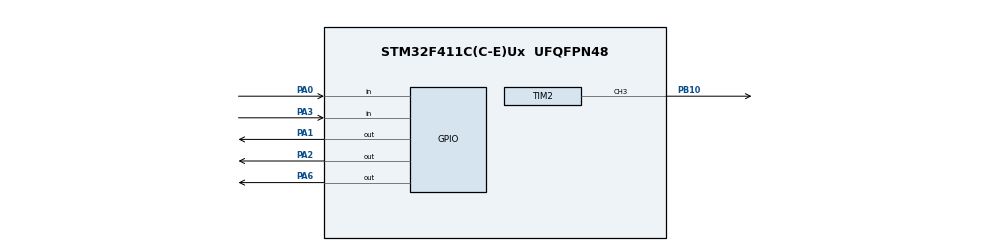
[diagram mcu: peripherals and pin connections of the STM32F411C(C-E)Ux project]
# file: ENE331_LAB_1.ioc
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Mcu.Family=STM32F4
Mcu.Name=STM32F411C(C-E)Ux
Mcu.Package=UFQFPN48
NVIC.PriorityGroup=NVIC_PRIORITYGROUP_4
NVIC.TIM2_IRQn=true\:0\:0\:false\:false\:true\:true\:true\:true
PA0-WKUP.Signal=GPIO_Input
PA1.Signal=GPIO_Output
PA13.Mode=Serial_Wire
PA13.Signal=SYS_JTMS-SWDIO
PA14.Mode=Serial_Wire
PA14.Signal=SYS_JTCK-SWCLK
PA2.Signal=GPIO_Output
PA3.Signal=GPIO_Input
PA6.PinState=GPIO_PIN_RESET
PA6.Signal=GPIO_Output
PB10.Signal=S_TIM2_CH3
PH0\ -\ OSC_IN.Mode=HSE-External-Oscillator
PH0\ -\ OSC_IN.Signal=RCC_OSC_IN
PH1\ -\ OSC_OUT.Mode=HSE-External-Oscillator
PH1\ -\ OSC_OUT.Signal=RCC_OSC_OUT
ProjectManager.HeapSize=0x200
ProjectManager.StackSize=0x400
ProjectManager.TargetToolchain=STM32CubeIDE
RCC.48MHZClocksFreq_Value=37500000
RCC.AHBFreq_Value=75000000
RCC.APB1CLKDivider=RCC_HCLK_DIV2
RCC.APB1Freq_Value=37500000
RCC.APB1TimFreq_Value=75000000
RCC.APB2Freq_Value=75000000
RCC.APB2TimFreq_Value=75000000
RCC.CortexFreq_Value=75000000
RCC.HCLKFreq_Value=75000000
RCC.HSE_VALUE=25000000
RCC.HSI_VALUE=16000000
RCC.LSE_VALUE=32768
RCC.PLLM=12
RCC.PLLN=72
RCC.PLLSourceVirtual=RCC_PLLSOURCE_HSE
RCC.SYSCLKFreq_VALUE=75000000
RCC.SYSCLKSource=RCC_SYSCLKSOURCE_PLLCLK
RCC.VCOOutputFreq_Value=150000000
SH.S_TIM2_CH3.0=TIM2_CH3,PWM Generation3 CH3
TIM2.Channel-PWM\ Generation3\ CH3=TIM_CHANNEL_3
TIM2.Period=1
TIM2.Prescaler=144-1
VP_TIM2_VS_ClockSourceINT.Mode=Internal
board=custom

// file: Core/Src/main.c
/* USER CODE BEGIN Header */
/**
  ******************************************************************************
  * @file           : main.c
  * @brief          : Main program body
  ******************************************************************************
  * @attention
  *
  * Copyright (c) 2025 STMicroelectronics.
  * All rights reserved.
  *
  * This software is licensed under terms that can be found in the LICENSE file
  * in the root directory of this software component.
  * If no LICENSE file comes with this software, it is provided AS-IS.
  *
  ******************************************************************************
  */
/* USER CODE END Header */
#include "main.h"

/* USER CODE BEGIN PM */
uint32_t Time_1;
uint32_t Settime_1 = 60; // กำหนดเวลาในการกระพริบ PA6 ทุกๆ 60 ticks (1.2 ms) , จากการคำนวณในรูป

uint32_t Time_2;
uint32_t Settime_2 = 1500;  // กำหนดเวลาในการอ่านค่าปุ่มทุกๆ 1500 ticks (20 ms)

uint32_t counter = 0; // นับเวลาโดยใช้ Timer

uint8_t state = 0;
uint8_t LUT[4] = {
	    0b001,  // State 0 → PA1 ON
	    0b010,  // State 1 → PA2 ON
	    0b100,  // State 2 → PA3 ON
	    0b111   // State 3 → All ON
};

void GPIOA_Config(void) {
	// Enable GPIOA Clock (if not already done)
	RCC->AHB1ENR |= RCC_AHB1ENR_GPIOAEN;

	// PA1–PA3: Set as general-purpose output
	GPIOA->MODER &= ~((0x3 << (1 * 2)) | (0x3 << (2 * 2)) | (0x3 << (3 * 2)));
	GPIOA->MODER |=  ((0x1 << (1 * 2)) | (0x1 << (2 * 2)) | (0x1 << (3 * 2))); // '01' = output

	// PA6
	GPIOA->MODER &= ~(0x3 << (6 * 2));  // Clear MODER6
	GPIOA->MODER |=  (0x2 << (6 * 2));  // '10'

	// Set ให้ output type ให้เป็น push-pull สำหรับ PA1, PA2, PA3, PA6
	GPIOA->OTYPER &= ~((1 << 1) | (1 << 2) | (1 << 3) | (1 << 6));

	// Set ให้ PA1, PA2, PA3, PA6 ให้ไม่มี pull-up หรือ pull-down
	GPIOA->PUPDR &= ~((0x3 << (1 * 2)) | (0x3 << (2 * 2)) | (0x3 << (3 * 2)) | (0x3 << (6 * 2)));

	// PA6 bits 27:24
	GPIOA->AFR[0] &= ~(0xF << (6 * 4));
	GPIOA->AFR[0] |=  (0x1 << (6 * 4));  // AF1
}
unsigned char Read_PA0(void) {
	return (GPIOA->IDR & (1 << 0)) ? 1 : 0; // ถ้า PA0 = 1(กด) คืนค่า 1, ถ้า PA0 = 0 คืนค่า 0
}

void GPIOB_Config(void) {
    // Enable GPIOB clock
    RCC->AHB1ENR |= (1 << 1);

    // MODER10 = B10
    GPIOB->MODER &= ~(0x3 << 20);  // Clear bits สำหรับ 21:20
    GPIOB->MODER |=  (0x2 << 20);  // Set bits 21:20 to 10

    // Set Alternate Function AF1 for TIM2_CH3 on PB10
    GPIOB->AFR[1] &= ~(0xF << 8);  // Clear bits สำหรับ PB10
    GPIOB->AFR[1] |=  (0x1 << 8);  // TIM2_CH3

    // Set push-pull and no pull-up/down
    GPIOB->OTYPER &= ~(1 << 10);    // Push-pull
    GPIOB->PUPDR  &= ~(0x3 << 20);  // No pull
}

void GPIO_Toggle_Config(void) {
    // Enable GPIOA Clock
    RCC -> AHB1ENR |= (0x01 << 0);  // Enable GPIOA clock

    // Set PA6 as output
    GPIOA -> MODER &= ~(0x03 << (6 * 2));  // Clear MODER6
    GPIOA -> MODER |= (0x01 << (6 * 2));   // Set PA6 as output ('01')

    // Set output type
    GPIOA -> OTYPER &= ~(0x01 << 6);  // set PA6 เป็น push-pull

    // Set GPIO Speed (optional)
    GPIOA -> OSPEEDR &= ~(0x03 << (6 * 2));  // set PA6 เป็นความเร็วต่ำ (default)

    // Disable pull-up/pull-down
    GPIOA -> PUPDR &= ~(0x03 << (6 * 2));   // ไม่มี pull-up หรือ pull-down สำหรับ PA6
}

void HAL_TIM_PeriodElapsedCallback(TIM_HandleTypeDef* htim) {
	if(htim -> Instance == TIM2) {
		counter++;
	}
}

/* USER CODE END PM */

TIM_HandleTypeDef htim2;

void SystemClock_Config(void);
static void MX_GPIO_Init(void);
static void MX_TIM2_Init(void);

int main(void)
{

  /* MCU Configuration--------------------------------------------------------*/

  /* Reset of all peripherals, Initializes the Flash interface and the Systick. */
  HAL_Init();

  /* Configure the system clock */
  SystemClock_Config();

  /* Initialize all configured peripherals */
  MX_GPIO_Init();
  MX_TIM2_Init();
  /* USER CODE BEGIN 2 */
  HAL_TIM_Base_Start(&htim2);
  GPIOA_Config();
  GPIOB_Config();
  GPIO_Toggle_Config();

  /* USER CODE END 2 */

  /* Infinite loop */
  /* USER CODE BEGIN WHILE */
  while (1)
  {

	     // 20 us base time from TIM2
	     if (__HAL_TIM_GET_FLAG(&htim2, TIM_FLAG_UPDATE) == SET) {
	         __HAL_TIM_CLEAR_FLAG(&htim2, TIM_FLAG_UPDATE);
	         counter++;
	     }
	        // ให้ PA6 กระพิบทุกๆ 1.2 ms
  	        if((counter - Time_1) >= Settime_1) {
	            // Your program task
	        	GPIOA-> ODR ^= (1 << 6); // Toggle PA6
	        	for(uint32_t i=0; i<=60000; i++) { // รอเวลาให้กระพริบ
	        		__NOP();
	        	}
	            Time_1 = counter; // update
		    }

	        // อ่านค่า PA0 และเปลี่ยน state ใน LUT
	        if((counter - Time_2) >= Settime_2) {
	            // Your program task
	        	 if ((Read_PA0() == 0 )) {
	        		// On falling edge (button press)
	        		GPIOA->ODR &= ~(0x0E);               // Clear ค่า PA1–PA3
	        		GPIOA->ODR |= (LUT[state] << 1);     // Update LED

	        		state += 1;

	        		if (state == 4){ // ถ้าเกิน state 3 reset ไป 0 ใหม่
	        			state = 0;}
	        		     	             }
	            Time_2 = counter; // update
		    }

    /* USER CODE END WHILE */

  }
}

void SystemClock_Config(void)
{
  RCC_OscInitTypeDef RCC_OscInitStruct = {0};
  RCC_ClkInitTypeDef RCC_ClkInitStruct = {0};

  /** Configure the main internal regulator output voltage
  */
  __HAL_RCC_PWR_CLK_ENABLE();
  __HAL_PWR_VOLTAGESCALING_CONFIG(PWR_REGULATOR_VOLTAGE_SCALE1);

  /** Initializes the RCC Oscillators according to the specified parameters
  * in the RCC_OscInitTypeDef structure.
  */
  RCC_OscInitStruct.OscillatorType = RCC_OSCILLATORTYPE_HSI;
  RCC_OscInitStruct.HSIState = RCC_HSI_ON;
  RCC_OscInitStruct.HSICalibrationValue = RCC_HSICALIBRATION_DEFAULT;
  RCC_OscInitStruct.PLL.PLLState = RCC_PLL_NONE;
  if (HAL_RCC_OscConfig(&RCC_OscInitStruct) != HAL_OK)
  {
    Error_Handler();
  }

  /** Initializes the CPU, AHB and APB buses clocks
  */
  RCC_ClkInitStruct.ClockType = RCC_CLOCKTYPE_HCLK|RCC_CLOCKTYPE_SYSCLK
                              |RCC_CLOCKTYPE_PCLK1|RCC_CLOCKTYPE_PCLK2;
  RCC_ClkInitStruct.SYSCLKSource = RCC_SYSCLKSOURCE_HSI;
  RCC_ClkInitStruct.AHBCLKDivider = RCC_SYSCLK_DIV1;
  RCC_ClkInitStruct.APB1CLKDivider = RCC_HCLK_DIV1;
  RCC_ClkInitStruct.APB2CLKDivider = RCC_HCLK_DIV1;

  if (HAL_RCC_ClockConfig(&RCC_ClkInitStruct, FLASH_LATENCY_0) != HAL_OK)
  {
    Error_Handler();
  }
}

static void MX_TIM2_Init(void)
{

  TIM_ClockConfigTypeDef sClockSourceConfig = {0};
  TIM_MasterConfigTypeDef sMasterConfig = {0};

  htim2.Instance = TIM2;
  htim2.Init.Prescaler = 1440-1;
  htim2.Init.CounterMode = TIM_COUNTERMODE_UP;
  htim2.Init.Period = 1;
  htim2.Init.ClockDivision = TIM_CLOCKDIVISION_DIV1;
  htim2.Init.AutoReloadPreload = TIM_AUTORELOAD_PRELOAD_DISABLE;
  if (HAL_TIM_Base_Init(&htim2) != HAL_OK)
  {
    Error_Handler();
  }
  sClockSourceConfig.ClockSource = TIM_CLOCKSOURCE_INTERNAL;
  if (HAL_TIM_ConfigClockSource(&htim2, &sClockSourceConfig) != HAL_OK)
  {
    Error_Handler();
  }
  sMasterConfig.MasterOutputTrigger = TIM_TRGO_RESET;
  sMasterConfig.MasterSlaveMode = TIM_MASTERSLAVEMODE_DISABLE;
  if (HAL_TIMEx_MasterConfigSynchronization(&htim2, &sMasterConfig) != HAL_OK)
  {
    Error_Handler();
  }

}

static void MX_GPIO_Init(void)
{
  GPIO_InitTypeDef GPIO_InitStruct = {0};

  /* GPIO Ports Clock Enable */
  __HAL_RCC_GPIOH_CLK_ENABLE();
  __HAL_RCC_GPIOA_CLK_ENABLE();
  __HAL_RCC_GPIOB_CLK_ENABLE();

  /*Configure GPIO pin Output Level */
  HAL_GPIO_WritePin(GPIOA, GPIO_PIN_1|GPIO_PIN_2|GPIO_PIN_3, GPIO_PIN_RESET);

  /*Configure GPIO pin Output Level */
  HAL_GPIO_WritePin(GPIOA, GPIO_PIN_6, GPIO_PIN_SET);

  /*Configure GPIO pin : PA0 */
  GPIO_InitStruct.Pin = GPIO_PIN_0;
  GPIO_InitStruct.Mode = GPIO_MODE_INPUT;
  GPIO_InitStruct.Pull = GPIO_PULLUP;
  HAL_GPIO_Init(GPIOA, &GPIO_InitStruct);

  /*Configure GPIO pins : PA1 PA2 PA3 PA6 */
  GPIO_InitStruct.Pin = GPIO_PIN_1|GPIO_PIN_2|GPIO_PIN_3|GPIO_PIN_6;
  GPIO_InitStruct.Mode = GPIO_MODE_OUTPUT_PP;
  GPIO_InitStruct.Pull = GPIO_NOPULL;
  GPIO_InitStruct.Speed = GPIO_SPEED_FREQ_LOW;
  HAL_GPIO_Init(GPIOA, &GPIO_InitStruct);

}

void Error_Handler(void)
{
  __disable_irq();
  while (1)
  {
  }
}
